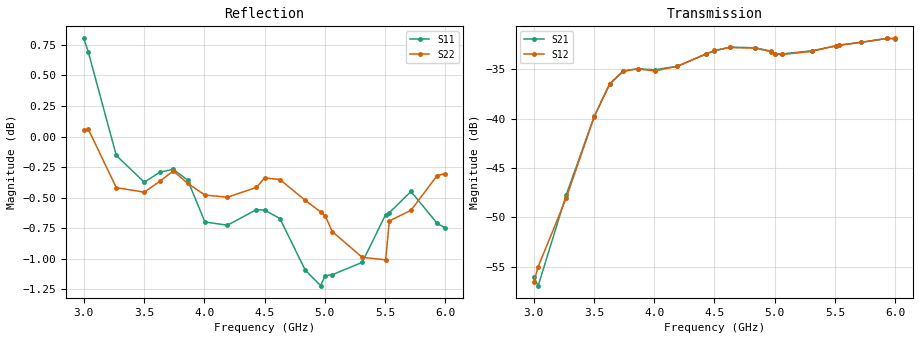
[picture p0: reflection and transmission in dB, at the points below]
!  27/11/2025  11:04:39
! Ref Plane: 0.000 mm
# MHZ S MA R  50
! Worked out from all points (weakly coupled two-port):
!   401 points, 3 GHz to 6 GHz, reference 50 ohm
!   highest |S21| = -31.88 dB at 5.933 GHz (marker M1); lowest = -56.9 dB at 3.038 GHz (marker M2)
!   lowest |S11| = -1.2 dB at 4.965 GHz (marker M3), VSWR 14.24, Z = 8.09 - j56.8 ohm
!   |S11| at or under -10 dB: nowhere
!   |S22| runs from -1.0 to 0.1 dB; largest |S21 - S12| = 0.00092
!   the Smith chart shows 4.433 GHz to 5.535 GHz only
!   S11 on the Smith chart (normalised r, x): 4.433 GHz: 0.07, +0.99; 4.628 GHz: 0.77, +4.29; 4.838 GHz: 0.47, -2.49; 5.062 GHz: 0.10, -0.70; 5.31 GHz: 0.06, -0.03; 5.535 GHz: 0.05, +0.59
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3000  1.097 -134.7  0.001582 48.5  0.001482 51.4  1.006 -102.0
3037.5  1.083 -144.7  0.001427 43.5  0.001783 44.9  1.007 -108.1
3270  0.9823 154.8  0.004117 -18.3  0.003964 -13.7  0.9529 -167.8
3502.5  0.9578 69.7  0.01028 -97.9  0.01021 -97.0  0.9489 115.5
3630  0.9669 14.4  0.01493 -153.5  0.01502 -152.2  0.9586 60.6
3742.5  0.9696 -35.7  0.01745 155.9  0.01735 157.6  0.9681 12.1
3862.5  0.9597 -83.6  0.01789 106.5  0.01787 108.2  0.9568 -36.6
4005  0.9226 -134.1  0.01768 57.0  0.01745 58.0  0.9463 -86.0
4192.5  0.9198 166.7  0.01843 -0.2  0.01841 1.4  0.9444 -144.1
4432.5  0.9334 90.5  0.02127 -74.6  0.0213 -72.6  0.9532 142.8
4500  0.933 67.7  0.02205 -96.6  0.02216 -95.3  0.9617 122.0
4627.5  0.9256 25.5  0.02301 -138.0  0.02293 -136.8  0.9603 82.5
4837.5  0.8817 -42.5  0.02286 154.9  0.02275 156.4  0.9416 18.7
4965  0.8688 -82.1  0.022 117.9  0.02187 119.2  0.9314 -17.5
5002.5  0.877 -93.4  0.02134 107.5  0.02121 108.7  0.9281 -29.0
5062.5  0.8779 -109.9  0.02127 91.0  0.02113 92.2  0.9142 -46.7
5310  0.8881 -176.6  0.02208 24.1  0.02192 25.4  0.8924 -117.6
5505  0.9291 126.2  0.0233 -29.8  0.02344 -28.2  0.8902 -169.2
5535  0.9307 119.2  0.02358 -37.6  0.02355 -36.3  0.9235 -176.6
5715  0.9495 66.8  0.02432 -89.9  0.02436 -88.2  0.9328 131.0
5932.5  0.9214 3.1  0.02547 -152.8  0.0255 -151.2  0.9639 73.5
6000  0.9174 -17.1  0.02535 -172.2  0.02548 -170.8  0.9656 56.2
